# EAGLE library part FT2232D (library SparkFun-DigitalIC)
USB to USART/FIFO/JTAG/SPI/I2C

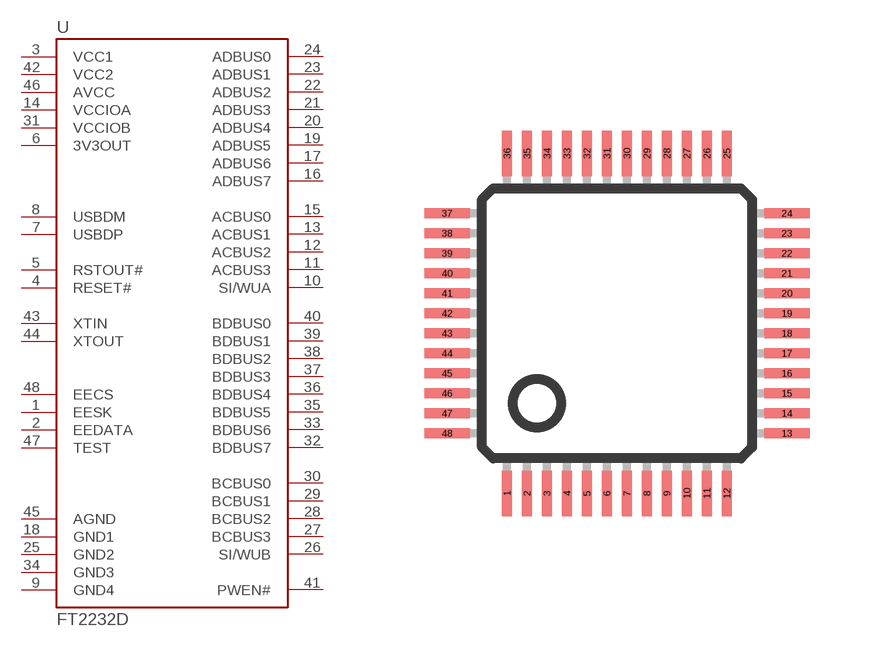
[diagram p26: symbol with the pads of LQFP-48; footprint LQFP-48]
Designator prefix -

## FT2232D  [LQFP-48]
1  EESK
2  EEDATA
3  VCC1  pwr
4  RESET#
5  RSTOUT#
6  3V3OUT  out
7  USBDP
8  USBDM
9  GND4
10  SI/WUA
11  ACBUS3
12  ACBUS2
13  ACBUS1
14  VCCIOA  pwr
15  ACBUS0
16  ADBUS7
17  ADBUS6
18  GND1  pwr
19  ADBUS5
20  ADBUS4
21  ADBUS3
22  ADBUS2
23  ADBUS1
24  ADBUS0
25  GND2  pwr
26  SI/WUB
27  BCBUS3
28  BCBUS2
29  BCBUS1
30  BCBUS0
31  VCCIOB
32  BDBUS7  in
33  BDBUS6  in
34  GND3  pwr
35  BDBUS5  in
36  BDBUS4  out
37  BDBUS3  in
38  BDBUS2  out
39  BDBUS1  in
40  BDBUS0  out
41  PWEN#
42  VCC2  pwr
43  XTIN
44  XTOUT
45  AGND  pwr
46  AVCC
47  TEST  in
48  EECS

## Footprint LQFP-48 (pad centres in mm)
smd 0.254 x 1.143: 1 -2.75,-4.25; 2 -2.25,-4.25; 3 -1.75,-4.25; 4 -1.25,-4.25; 5 -0.75,-4.25; 6 -0.25,-4.25; 7 0.25,-4.25; 8 0.75,-4.25; 9 1.25,-4.25; 10 1.75,-4.25; 11 2.25,-4.25; 12 2.75,-4.25; 25 2.75,4.25; 26 2.25,4.25; 27 1.75,4.25; 28 1.25,4.25; 29 0.75,4.25; 30 0.25,4.25; 31 -0.25,4.25; 32 -0.75,4.25; 33 -1.25,4.25; 34 -1.75,4.25; 35 -2.25,4.25; 36 -2.75,4.25
smd 1.143 x 0.254: 13 4.25,-2.75; 14 4.25,-2.25; 15 4.25,-1.75; 16 4.25,-1.25; 17 4.25,-0.75; 18 4.25,-0.25; 19 4.25,0.25; 20 4.25,0.75; 21 4.25,1.25; 22 4.25,1.75; 23 4.25,2.25; 24 4.25,2.75; 37 -4.25,2.75; 38 -4.25,2.25; 39 -4.25,1.75; 40 -4.25,1.25; 41 -4.25,0.75; 42 -4.25,0.25; 43 -4.25,-0.25; 44 -4.25,-0.75; 45 -4.25,-1.25; 46 -4.25,-1.75; 47 -4.25,-2.25; 48 -4.25,-2.75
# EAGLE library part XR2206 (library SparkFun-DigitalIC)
XR2206 Monolithic Function Generator

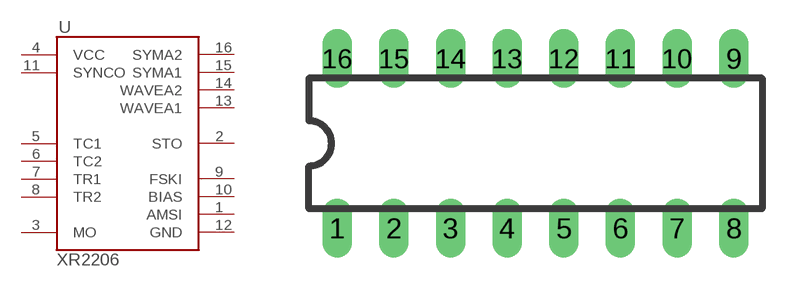
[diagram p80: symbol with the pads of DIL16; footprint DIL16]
Designator prefix U

## XR2206  [DIL16]
1  AMSI  in
2  STO  out
3  MO  out
4  VCC  pwr
5  TC1  in
6  TC2  in
7  TR1  out
8  TR2  out
9  FSKI  in
10  BIAS  out
11  SYNCO  out
12  GND  pwr
13  WAVEA1  in
14  WAVEA2  in
15  SYMA1  in
16  SYMA2  in

## Footprint DIL16 (pad centres in mm)
Dual In Line Package
drill 0.813 long: 1 -8.89,-3.81; 2 -6.35,-3.81; 3 -3.81,-3.81; 4 -1.27,-3.81; 5 1.27,-3.81; 6 3.81,-3.81; 7 6.35,-3.81; 8 8.89,-3.81; 9 8.89,3.81; 10 6.35,3.81; 11 3.81,3.81; 12 1.27,3.81; 13 -1.27,3.81; 14 -3.81,3.81; 15 -6.35,3.81; 16 -8.89,3.81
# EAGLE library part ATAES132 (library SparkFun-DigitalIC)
32Kb Serial EEPROM. AES-128-CCM. MAC. Secure Storage for 128-bit keys. Encrypted User Memory Readn and Write. HWRNG. 2.5V to 5.5V.

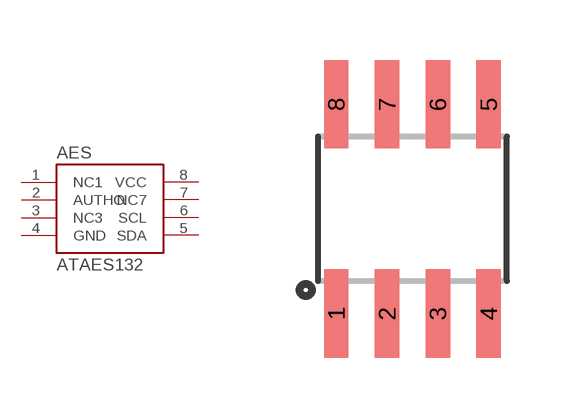
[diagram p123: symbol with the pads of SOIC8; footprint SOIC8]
Designator prefix AES

## ATAES132 (PROD_ID: IC-11983)  [SOIC8]
1  NC1  nc
2  AUTHO
3  NC3  nc
4  GND  pwr
5  SDA
6  SCL
7  NC7  nc
8  VCC  pwr

## Footprint SOIC8 (pad centres in mm)
SOIC 8-Lead
smd 0.61 x 2.21: 1 -1.905,-2.616; 2 -0.635,-2.616; 3 0.635,-2.616; 4 1.905,-2.616; 5 1.905,2.616; 6 0.635,2.616; 7 -0.635,2.616; 8 -1.905,2.616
